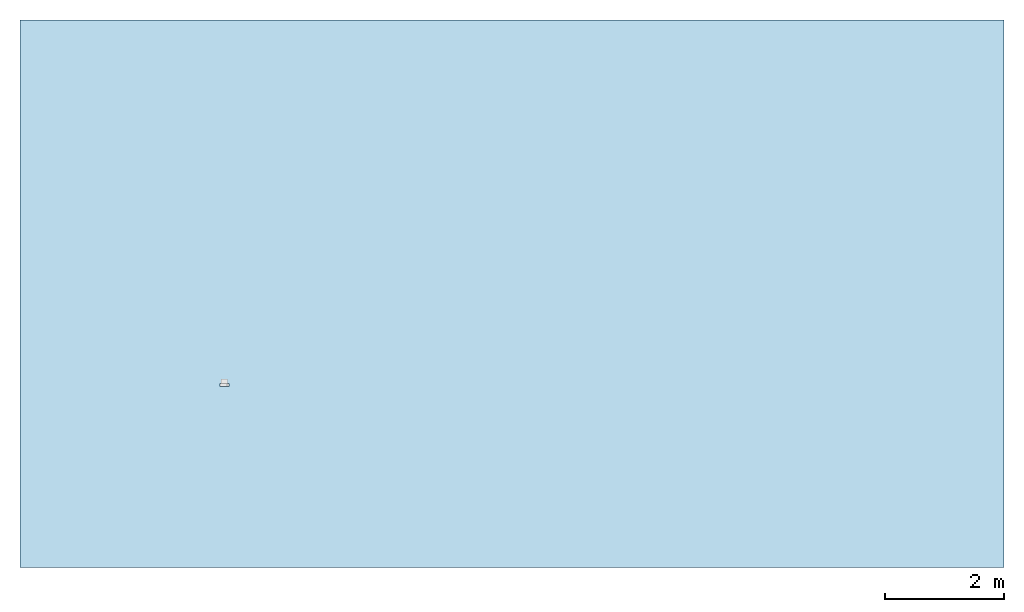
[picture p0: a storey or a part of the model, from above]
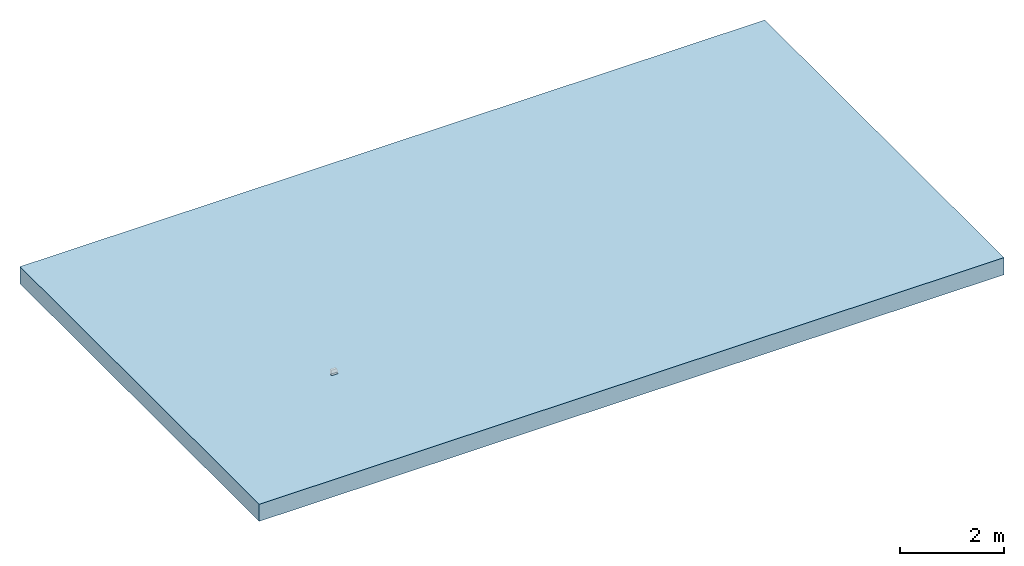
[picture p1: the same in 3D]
Properties of the parts of a building model (IFC2X3)

# File
Description: ViewDefinition [CoordinationView]
File name: 4238 - RH inlet-outlet end cap.ifc
Time: 2013-09-02T12:43:54
Written by: Autodesk Revit 2013
Made in: 20120221_2030(x64)

# IfcProject, Project Number
LongName: Project Name; Phase: Project Status

# IfcSite, Default
RefLatitude: 42, 21, 30, 344238; RefLongitude: -71, -3, -35, -194702; RefElevation: 0 mm

# IfcBuilding
Pset_BuildingCommon - NumberOfStoreys: 1
Other - Project Number: Project Number; Project Status: Project Status; Client Name: Owner; Project Issue Date: Issue Date; Project Address: ## Street City, State Zip; Project Name: Project Name

# IfcBuildingStorey, Level 1
LongName: Level 1; Elevation: 0 mm
Constraints - Elevation Base: 0; Elevation: 0 mm
Graphics - Line Weight: 1; Symbol: M_Level Head - Circle: M_Level Head - Circle; Color: 0; Symbol at End 2 Default: yes; Line Pattern: Center; Symbol at End 1 Default: no
Identity Data - Structural: no; Building Story: yes; Name: Level 1
Dimensions - Computation Height: 0 mm

# IfcBuildingElementProxy: 4238 - RH inlet/outlet end cap, Civil-Drainage-Channel-ACO-KerbDrain-HB405:4238 - RH inlet/outlet end cap:4238 - RH inlet/outlet end cap:312781
In: Level 1
Material: Orange, ACO Polymer Concrete.
Other - Revision: 1; CreatedBy: www.aco.co.uk
Constraints - Level: Level: Level 1; Moves With Nearby Elements: no
Phasing - Phase Created: New Construction
Dimensions - Volume: 2699488 mm3; Circular Void Depth: 329.966 mm; Void Length: 50 mm; Void Width: 150 mm; Void Depth: -280 mm
Pset_BuildingElementProxyCommon - Reference: 4238 - RH inlet/outlet end cap
General - SerialNumber: 0.000000; TagNumber: 0.000000
Materials and Finishes - Connection Pipe Material Colour: Brown; Channel Material: N/A; End Cap Material: Vienite® Synthetic Resin Concrete; Access Cover/Frame Finish: N/A; End Cap Colour: Grey; Channel Colour: N/A; Access Cover/Frame Material: N/A; Connection Pipe Material: PVCu; Access Cover/Frame Colour: N/A
Construction - RH drop kerb: no; LH inlet/outlet end cap: no; LH drop kerb: no; HB405 - 500: no; Centre Stone: no; Access Unit: no; HB405 500_blindunit: no; RH inlet/outlet end cap: yes; HB405 - 1000: no; Closing end cap: no
Data - Invert Depth: N/A; Product Weight: 5.7 Kg; Channel C.S.A: N/A; Drainage Slot Width: N/A; Installation - Concrete Grade: N/A; Product Dimensions: 50mm x 150mm x 405mm (LxWxH); Load Class: N/A; Drainage Slot Intake area: N/A; Product Standard: N/A; Hydraulic Performance: N/A; Connection Pipe O.D: Ø110mm; Concrete Surround Volume - Load Class A 15 - D 400 - Concrete Pavement: N/A; Concrete Surround Volume - Load Class A 15 - D 400 - Grass or Asphalt Pavement: N/A; ACO Hydraulic Design Software: N/A
Green Building Properties - Channel Recyclable: N/A; End Cap Recyclable: Fully recyclable; Access Cover/Frame Recyclable: N/A; Channel Recycled Material Content: N/A; End Cap Recycled Material Content: 20% minimum; Access Cover/Frame Recycled Material Content: N/A
Identity Data - Product Code: 4238; Fax: +44 (0)1462 815895; e-mail Sales: customersupport@aco.co.uk; OmniClass Title: Rainwater Removal; Model Description: Combined kerb and drainage system; Price: POA - contact ACO; OmniClass Number: 23.70.50.24; Model: ACO KerbDrain HB405; Installation guidelines: http://www.aco.co.uk/download.php?id=120; e-mail Technical: technical@aco.co.uk; Product brochure: http://www.aco.co.uk/download.php?id=120; Telephone: +44 (0)1462 816666; Manufacturer: ACO Technologies plc - ACO Water Management Division; Address: ACO Business Park, Hitchin Road, Shefford, Bedfordshire, United Kingdom SG17 5TE; Assembly Description: Rain Water Drainage; Product Page URL: http://www.aco.co.uk/product_detail.php?id=3; URL: www.aco.co.uk; Cost: 0; Type Comments: ACO KerbDrain HB405 half battered RH outlet end cap; Maintenance guidelines: http://www.aco.co.uk/download.php?id=120; Assembly Code: D2040

# IfcOpeningElement: Recess
In: Level 1
Constraints - Related to Mass: no; Height Offset From Level: 0 mm; Level: Level: Level 1; Room Bounding: yes
Phasing - Phase Created: New Construction
Dimensions - Thickness: 400 mm; Volume: 60585191728 mm3; Perimeter: 51360 mm; Area: 151470000 mm2
Structural - Enable Analytical Model: no; Structural: no
Construction - Function: 0; Default Thickness: 400 mm
Analytical Properties - Roughness: 1; Absorptance: 0.1
Graphics - Coarse Scale Fill Color: 0
Materials and Finishes - Structural Material: Plant

# IfcSlab: Floor:Generic Floor - 400mm, Floor:Generic Floor - 400mm:193825
In: Level 1
PredefinedType: FLOOR; Material: Plant 400 mm
Constraints - Related to Mass: no; Height Offset From Level: 0 mm; Level: Level: Level 1; Room Bounding: yes
Phasing - Phase Created: New Construction
Dimensions - Thickness: 400 mm; Volume: 60585191728 mm3; Perimeter: 51360 mm; Area: 151470000 mm2
Structural - Enable Analytical Model: no; Structural: no
Pset_SlabCommon - Reference: Generic Floor - 400mm; IsExternal: no; LoadBearing: yes
Construction - Function: 0; Default Thickness: 400 mm
Analytical Properties - Roughness: 1; Absorptance: 0.1
Graphics - Coarse Scale Fill Color: 0
Materials and Finishes - Structural Material: Plant
